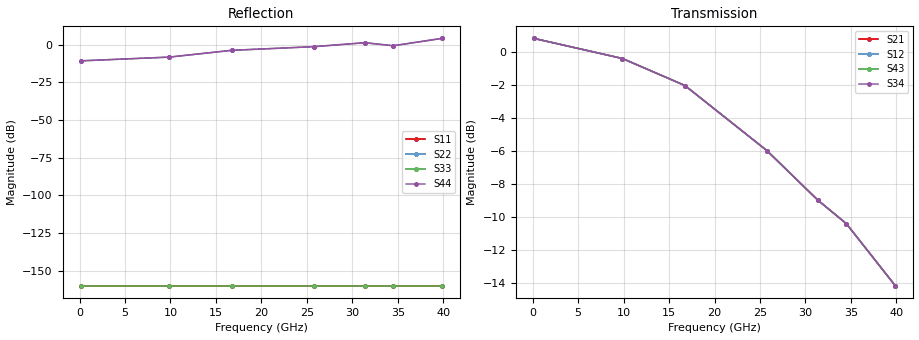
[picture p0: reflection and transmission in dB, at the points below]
! 26-Jun-2017 15:42:17
# Hz S RI R 50
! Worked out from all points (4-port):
!   319 points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, 125 MHz to 39.88 GHz, reference 50 ohm
!   strongest paths, dB at 125 MHz, 10 GHz, 20 GHz, 30 GHz, 39.88 GHz:
!     S43: 0.8, -0.4, -3.3, -8.4, -14.2
!     S21: 0.8, -0.4, -3.3, -8.4, -14.2
!     S42: -, -, -, -, -
!     S41: -, -, -, -, -
!     S32: -, -, -, -, -
!     S31: -, -, -, -, -
!   lowest |S11| = - dB at 125 MHz (marker M1), VSWR 1.00, Z = 50 + j0 ohm
!   |S11| at or under -10 dB: start of sweep to end of sweep
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1.25e8  0 0  1.102 -0.0284  0 0  0 0
        1.102 -0.0284  -0.2875 -0.00531  0 0  0 0
        0 0  0 0  0 0  1.102 -0.0284
        0 0  0 0  1.102 -0.0284  -0.2875 -0.00531
9.875e9  0 0  0.0629 -0.9554  0 0  0 0
         0.0629 -0.9554  -0.3827 0.0209  0 0  0 0
         0 0  0 0  0 0  0.0629 -0.9554
         0 0  0 0  0.0629 -0.9554  -0.3827 0.0209
1.675e10  0 0  -0.7107 -0.3505  0 0  0 0
          -0.7107 -0.3505  -0.6384 0.0743  0 0  0 0
          0 0  0 0  0 0  -0.7107 -0.3505
          0 0  0 0  -0.7107 -0.3505  -0.6384 0.0743
2.575e10  0 0  -0.3107 0.3954  0 0  0 0
          -0.3107 0.3954  -0.8316 0.1715  0 0  0 0
          0 0  0 0  0 0  -0.3107 0.3954
          0 0  0 0  -0.3107 0.3954  -0.8316 0.1715
3.1375e10  0 0  0.0202 0.3545  0 0  0 0
           0.0202 0.3545  -0.9113 0.7007  0 0  0 0
           0 0  0 0  0 0  0.0202 0.3545
           0 0  0 0  0.0202 0.3545  -0.9113 0.7007
3.45e10  0 0  0.1421 0.2658  0 0  0 0
         0.1421 0.2658  -0.7354 0.5395  0 0  0 0
         0 0  0 0  0 0  0.1421 0.2658
         0 0  0 0  0.1421 0.2658  -0.7354 0.5395
3.9875e10  0 0  0.1832 0.0676  0 0  0 0
           0.1832 0.0676  -1.476 0.6234  0 0  0 0
           0 0  0 0  0 0  0.1832 0.0676
           0 0  0 0  0.1832 0.0676  -1.476 0.6234
